# Synthetic checker fixture. Dimensions mirror only the demonstrated geometric
# interface, not a complete process technology or a sign-off rule deck.
VERSION 5.8 ;
BUSBITCHARS "[]" ;
DIVIDERCHAR "/" ;
UNITS
  DATABASE MICRONS 2000 ;
END UNITS
MANUFACTURINGGRID 0.005 ;
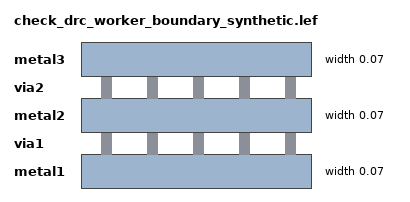
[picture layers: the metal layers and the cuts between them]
LAYER metal1
  TYPE ROUTING ; DIRECTION HORIZONTAL ;
  WIDTH 0.07 ; PITCH 0.14 ; SPACING 0.07 ;
END metal1
LAYER via1
  TYPE CUT ; WIDTH 0.07 ; SPACING 0.08 ;
END via1
LAYER metal2
  TYPE ROUTING ; DIRECTION VERTICAL ;
  WIDTH 0.07 ; PITCH 0.19 ;
  SPACINGTABLE PARALLELRUNLENGTH 0.0 WIDTH 0.0 0.07 ;
END metal2
LAYER via2
  TYPE CUT ; WIDTH 0.07 ; SPACING 0.09 ;
END via2
LAYER metal3
  TYPE ROUTING ; DIRECTION HORIZONTAL ;
  WIDTH 0.07 ; PITCH 0.14 ;
  SPACINGTABLE PARALLELRUNLENGTH 0.0 WIDTH 0.0 0.07 ;
END metal3
VIA via1_4 DEFAULT
  LAYER metal1 ; RECT -0.035 -0.070 0.035 0.070 ;
  LAYER via1 ; RECT -0.035 -0.035 0.035 0.035 ;
  LAYER metal2 ; RECT -0.035 -0.070 0.035 0.070 ;
END via1_4
VIA via2_5 DEFAULT
  LAYER metal2 ; RECT -0.035 -0.070 0.035 0.070 ;
  LAYER via2 ; RECT -0.035 -0.035 0.035 0.035 ;
  LAYER metal3 ; RECT -0.070 -0.035 0.070 0.035 ;
END via2_5
END LIBRARY
